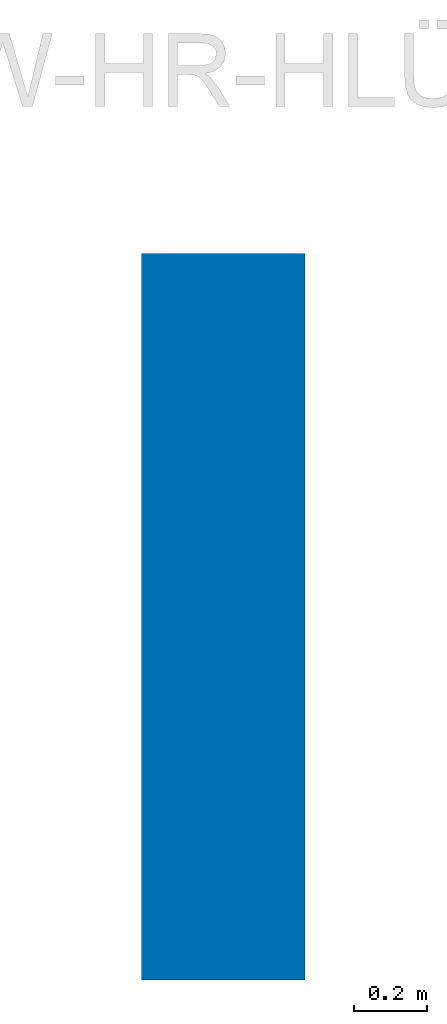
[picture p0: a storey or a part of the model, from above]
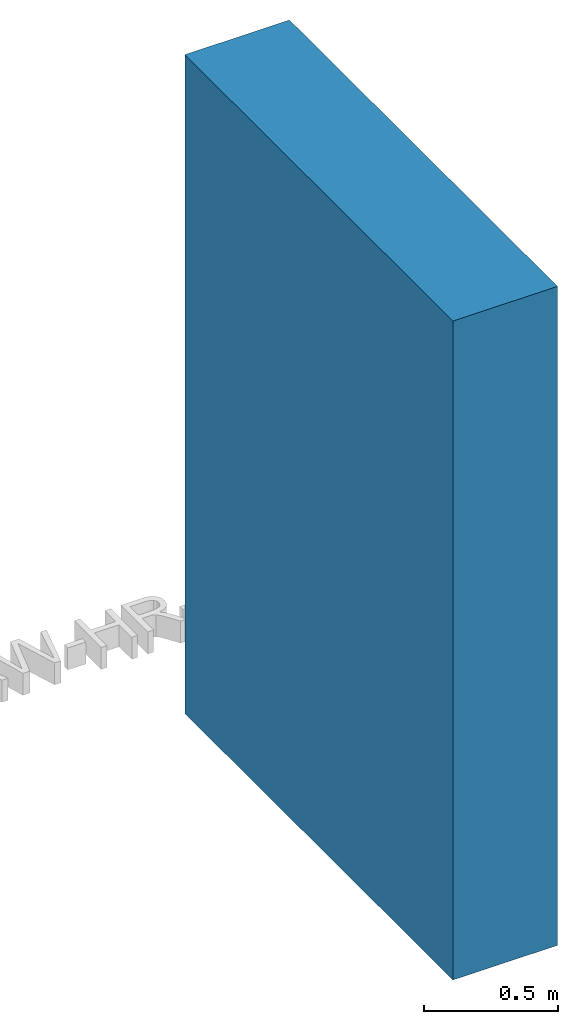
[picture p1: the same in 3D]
Properties of the parts of a building model (IFC2X3)

# File
Description: ViewDefinition [CoordinationView_V2.0], ExchangeRequirement [Architecture]
File name: 2018_01
Time: 2023-07-17T09:54:46+01:00
Written by: ODA SDAI 22.12
Made in: 23.0.11.19 - Exporter 23.0.11.19 - Alternativ-UI 23.0.11.19

# IfcProject, 2018_01
Phase: Projekt Status

# IfcSite, Default
RefLatitude: 48, 8, 15, 359802; RefLongitude: 11, 34, 47, 783432; RefElevation: 0 m

# IfcBuildingElementProxy: Modelltext:600mm Arial, Modelltext:600mm Arial:2498057
In: Default
Pset_BuildingElementProxyCommon - Reference: 600mm Arial; sets with these values: 2
Pset_ProvisionForVoid - Shape: Undefined; Width: 0.0251141 m; Height: 0.0251141 m; Depth: 0.1 m

# IfcWallStandardCase: Basiswand:fbimSg_Wall_lb_WOD_vis_at_NTR_natuREbuilt_AW-HR-HLÜ-VS_GK4, Basiswand:fbimSg_Wall_lb_WOD_vis_at_NTR_natuREbuilt_AW-HR-HLÜ-VS_GK4:2498170
In: Default
Type - PredefinedType: STANDARD; Material: fbim_12400515_AT_025_Vollholz_Bretter_Laerche 0.019 m, fbim_14100590_AT_001_Luftschicht 0.04 m, fbim_16101505_AT_001_Gipsfaserplatte_12.5mm 0.015 m, fbim_14104515_AT_090_Zellulose_Einblasdaemmung 0.28 m, fbim_12401520_AT_001_OSB_Platte 0.018 m, fbim_16101505_AT_001_Gipsfaserplatte_12.5mm 0.0125 m, fbim_14100505_AT_002_Schafwolle 0.04 m, fbim_16101505_AT_001_Gipsfaserplatte_12.5mm 0.0125 m, fbim_16101505_AT_001_Gipsfaserplatte_12.5mm 0.0125 m, fbim_16106515_AT_001_Gipsspachtel 0.001 m
Type - Pset_WallCommon - IsExternal: no
Pset_QuantityTakeOff - Reference: fbimSg_Wall_lb_WOD_vis_at_NTR_natuREbuilt_AW-HR-HLÜ-VS_GK4; sets with these values: 2
Pset_WallCommon - Reference: fbimSg_Wall_lb_WOD_vis_at_NTR_natuREbuilt_AW-HR-HLÜ-VS_GK4; ExtendToStructure: no; LoadBearing: no
